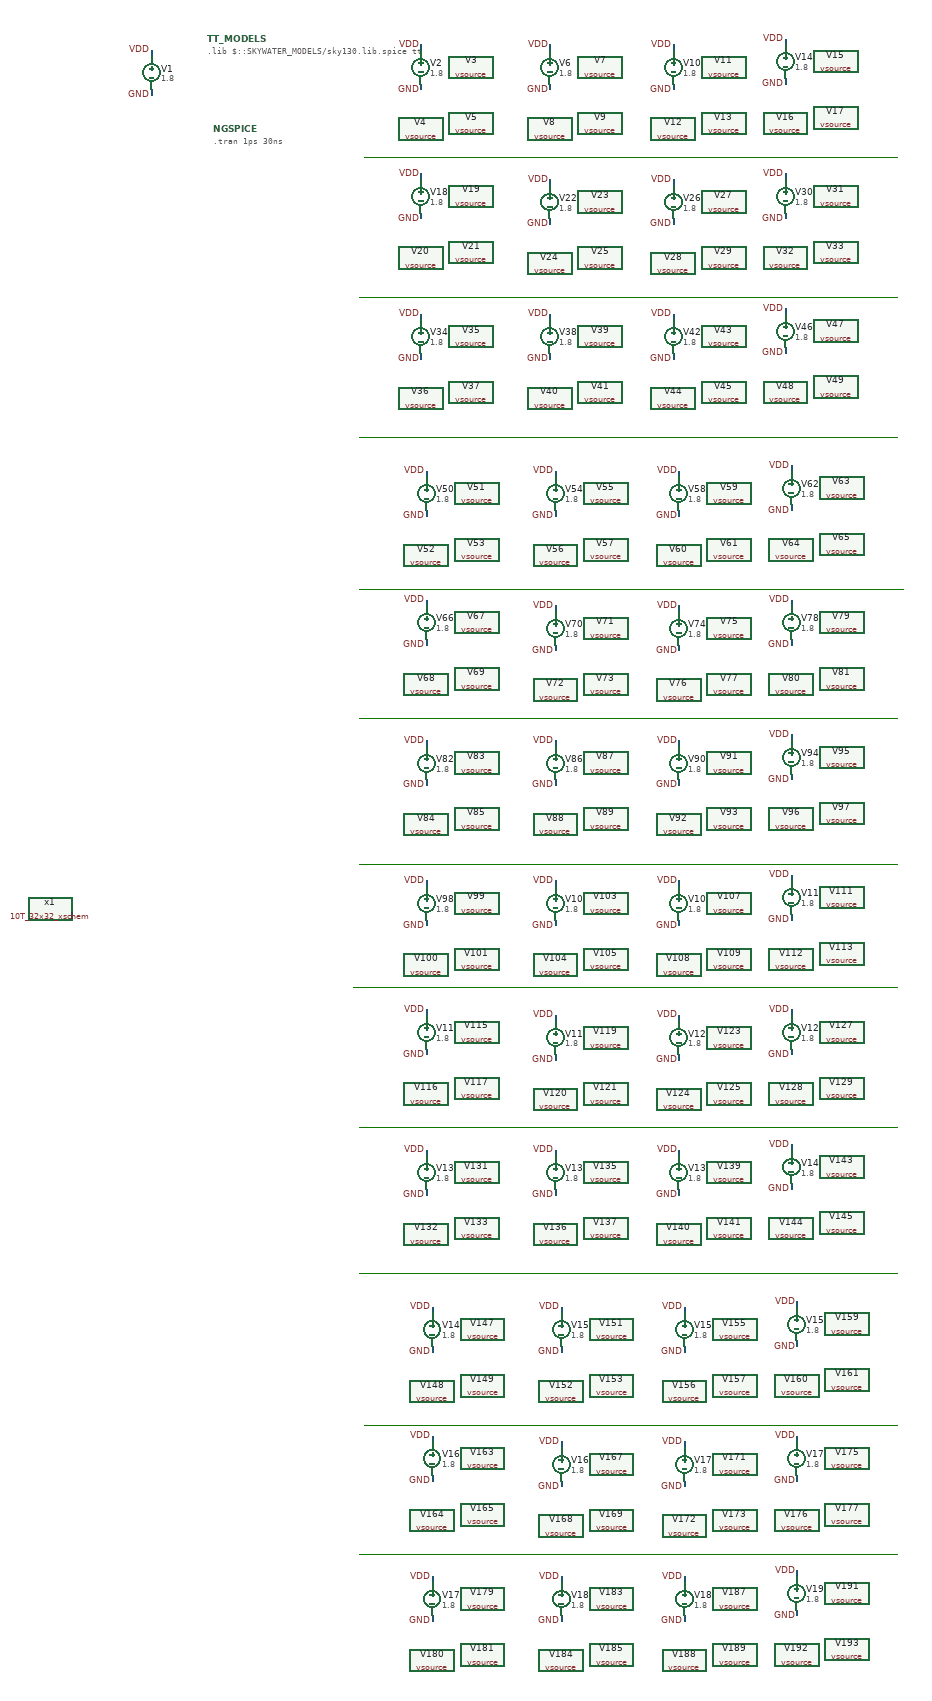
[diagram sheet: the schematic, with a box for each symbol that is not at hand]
v {xschem version=3.0.0 file_version=1.2 }
G {}
K {}
V {}
S {}
E {}
L 4 560 -1500 1510 -1500 {}
L 4 550 -1250 1510 -1250 {}
L 4 550 -1000 1510 -1000 {}
L 4 550 -730 1520 -730 {}
L 4 550 -500 1510 -500 {}
L 4 550 -240 1510 -240 {}
L 4 540 -20 1510 -20 {}
L 4 550 230 1510 230 {}
L 4 550 490 1510 490 {}
L 4 560 760 1510 760 {}
L 4 550 990 1510 990 {}
N 180 -1690 180 -1680 {
lab=VDD}
N 180 -1620 180 -1610 {
lab=GND}
N 660 -1700 660 -1690 {
lab=VDD}
N 660 -1630 660 -1620 {
lab=GND}
N 890 -1700 890 -1690 {
lab=VDD}
N 890 -1630 890 -1620 {
lab=GND}
N 1110 -1700 1110 -1690 {
lab=VDD}
N 1110 -1630 1110 -1620 {
lab=GND}
N 1310 -1710 1310 -1700 {
lab=VDD}
N 1310 -1640 1310 -1630 {
lab=GND}
N 660 -1470 660 -1460 {
lab=VDD}
N 660 -1400 660 -1390 {
lab=GND}
N 890 -1460 890 -1450 {
lab=VDD}
N 890 -1390 890 -1380 {
lab=GND}
N 1110 -1460 1110 -1450 {
lab=VDD}
N 1110 -1390 1110 -1380 {
lab=GND}
N 1310 -1470 1310 -1460 {
lab=VDD}
N 1310 -1400 1310 -1390 {
lab=GND}
N 660 -1220 660 -1210 {
lab=VDD}
N 660 -1150 660 -1140 {
lab=GND}
N 890 -1220 890 -1210 {
lab=VDD}
N 890 -1150 890 -1140 {
lab=GND}
N 1110 -1220 1110 -1210 {
lab=VDD}
N 1110 -1150 1110 -1140 {
lab=GND}
N 1310 -1230 1310 -1220 {
lab=VDD}
N 1310 -1160 1310 -1150 {
lab=GND}
N 670 -940 670 -930 {
lab=VDD}
N 670 -870 670 -860 {
lab=GND}
N 900 -940 900 -930 {
lab=VDD}
N 900 -870 900 -860 {
lab=GND}
N 1120 -940 1120 -930 {
lab=VDD}
N 1120 -870 1120 -860 {
lab=GND}
N 1320 -950 1320 -940 {
lab=VDD}
N 1320 -880 1320 -870 {
lab=GND}
N 670 -710 670 -700 {
lab=VDD}
N 670 -640 670 -630 {
lab=GND}
N 900 -700 900 -690 {
lab=VDD}
N 900 -630 900 -620 {
lab=GND}
N 1120 -700 1120 -690 {
lab=VDD}
N 1120 -630 1120 -620 {
lab=GND}
N 1320 -710 1320 -700 {
lab=VDD}
N 1320 -640 1320 -630 {
lab=GND}
N 670 -460 670 -450 {
lab=VDD}
N 670 -390 670 -380 {
lab=GND}
N 900 -460 900 -450 {
lab=VDD}
N 900 -390 900 -380 {
lab=GND}
N 1120 -460 1120 -450 {
lab=VDD}
N 1120 -390 1120 -380 {
lab=GND}
N 1320 -470 1320 -460 {
lab=VDD}
N 1320 -400 1320 -390 {
lab=GND}
N 670 -210 670 -200 {
lab=VDD}
N 670 -140 670 -130 {
lab=GND}
N 900 -210 900 -200 {
lab=VDD}
N 900 -140 900 -130 {
lab=GND}
N 1120 -210 1120 -200 {
lab=VDD}
N 1120 -140 1120 -130 {
lab=GND}
N 1320 -220 1320 -210 {
lab=VDD}
N 1320 -150 1320 -140 {
lab=GND}
N 670 20 670 30 {
lab=VDD}
N 670 90 670 100 {
lab=GND}
N 900 30 900 40 {
lab=VDD}
N 900 100 900 110 {
lab=GND}
N 1120 30 1120 40 {
lab=VDD}
N 1120 100 1120 110 {
lab=GND}
N 1320 20 1320 30 {
lab=VDD}
N 1320 90 1320 100 {
lab=GND}
N 670 270 670 280 {
lab=VDD}
N 670 340 670 350 {
lab=GND}
N 900 270 900 280 {
lab=VDD}
N 900 340 900 350 {
lab=GND}
N 1120 270 1120 280 {
lab=VDD}
N 1120 340 1120 350 {
lab=GND}
N 1320 260 1320 270 {
lab=VDD}
N 1320 330 1320 340 {
lab=GND}
N 680 550 680 560 {
lab=VDD}
N 680 620 680 630 {
lab=GND}
N 910 550 910 560 {
lab=VDD}
N 910 620 910 630 {
lab=GND}
N 1130 550 1130 560 {
lab=VDD}
N 1130 620 1130 630 {
lab=GND}
N 1330 540 1330 550 {
lab=VDD}
N 1330 610 1330 620 {
lab=GND}
N 680 780 680 790 {
lab=VDD}
N 680 850 680 860 {
lab=GND}
N 910 790 910 800 {
lab=VDD}
N 910 860 910 870 {
lab=GND}
N 1130 790 1130 800 {
lab=VDD}
N 1130 860 1130 870 {
lab=GND}
N 1330 780 1330 790 {
lab=VDD}
N 1330 850 1330 860 {
lab=GND}
N 680 1030 680 1040 {
lab=VDD}
N 680 1100 680 1110 {
lab=GND}
N 910 1030 910 1040 {
lab=VDD}
N 910 1100 910 1110 {
lab=GND}
N 1130 1030 1130 1040 {
lab=VDD}
N 1130 1100 1130 1110 {
lab=GND}
N 1330 1020 1330 1030 {
lab=VDD}
N 1330 1090 1330 1100 {
lab=GND}
C {10T_32x32_xschem.sym} 0 -160 0 0 {name=x1}
C {devices/vsource.sym} 180 -1650 0 0 {name=V1 value=1.8}
C {devices/lab_pin.sym} 180 -1690 0 0 {name=l8 sig_type=std_logic lab=VDD}
C {devices/lab_pin.sym} 180 -1610 0 0 {name=l9 sig_type=std_logic lab=GND}
C {devices/code_shown.sym} 290 -1550 0 0 {name=NGSPICE
only_toplevel=true
place=end
value="
.tran 1ps 30ns
"}
C {devices/code.sym} 280 -1710 0 0 {name=TT_MODELS
only_toplevel=true
format="tcleval( @value )"
value="
.lib $::SKYWATER_MODELS/sky130.lib.spice tt

"}
C {devices/vsource.sym} 660 -1660 0 0 {name=V2 value=1.8}
C {devices/lab_pin.sym} 660 -1700 0 0 {name=l1 sig_type=std_logic lab=VDD}
C {devices/lab_pin.sym} 660 -1620 0 0 {name=l2 sig_type=std_logic lab=GND}
C {devices/vsource.sym} 750 -1660 0 0 {name=V3 value=1.8}
C {devices/vsource.sym} 660 -1550 0 0 {name=V4 value=1.8}
C {devices/vsource.sym} 750 -1560 0 0 {name=V5 value=1.8}
C {devices/vsource.sym} 890 -1660 0 0 {name=V6 value=1.8}
C {devices/lab_pin.sym} 890 -1700 0 0 {name=l3 sig_type=std_logic lab=VDD}
C {devices/lab_pin.sym} 890 -1620 0 0 {name=l4 sig_type=std_logic lab=GND}
C {devices/vsource.sym} 980 -1660 0 0 {name=V7 value=1.8}
C {devices/vsource.sym} 890 -1550 0 0 {name=V8 value=1.8}
C {devices/vsource.sym} 980 -1560 0 0 {name=V9 value=1.8}
C {devices/vsource.sym} 1110 -1660 0 0 {name=V10 value=1.8}
C {devices/lab_pin.sym} 1110 -1700 0 0 {name=l5 sig_type=std_logic lab=VDD}
C {devices/lab_pin.sym} 1110 -1620 0 0 {name=l6 sig_type=std_logic lab=GND}
C {devices/vsource.sym} 1200 -1660 0 0 {name=V11 value=1.8}
C {devices/vsource.sym} 1110 -1550 0 0 {name=V12 value=1.8}
C {devices/vsource.sym} 1200 -1560 0 0 {name=V13 value=1.8}
C {devices/vsource.sym} 1310 -1670 0 0 {name=V14 value=1.8}
C {devices/lab_pin.sym} 1310 -1710 0 0 {name=l7 sig_type=std_logic lab=VDD}
C {devices/lab_pin.sym} 1310 -1630 0 0 {name=l10 sig_type=std_logic lab=GND}
C {devices/vsource.sym} 1400 -1670 0 0 {name=V15 value=1.8}
C {devices/vsource.sym} 1310 -1560 0 0 {name=V16 value=1.8}
C {devices/vsource.sym} 1400 -1570 0 0 {name=V17 value=1.8}
C {devices/vsource.sym} 660 -1430 0 0 {name=V18 value=1.8}
C {devices/lab_pin.sym} 660 -1470 0 0 {name=l11 sig_type=std_logic lab=VDD}
C {devices/lab_pin.sym} 660 -1390 0 0 {name=l12 sig_type=std_logic lab=GND}
C {devices/vsource.sym} 750 -1430 0 0 {name=V19 value=1.8}
C {devices/vsource.sym} 660 -1320 0 0 {name=V20 value=1.8}
C {devices/vsource.sym} 750 -1330 0 0 {name=V21 value=1.8}
C {devices/vsource.sym} 890 -1420 0 0 {name=V22 value=1.8}
C {devices/lab_pin.sym} 890 -1460 0 0 {name=l13 sig_type=std_logic lab=VDD}
C {devices/lab_pin.sym} 890 -1380 0 0 {name=l14 sig_type=std_logic lab=GND}
C {devices/vsource.sym} 980 -1420 0 0 {name=V23 value=1.8}
C {devices/vsource.sym} 890 -1310 0 0 {name=V24 value=1.8}
C {devices/vsource.sym} 980 -1320 0 0 {name=V25 value=1.8}
C {devices/vsource.sym} 1110 -1420 0 0 {name=V26 value=1.8}
C {devices/lab_pin.sym} 1110 -1460 0 0 {name=l15 sig_type=std_logic lab=VDD}
C {devices/lab_pin.sym} 1110 -1380 0 0 {name=l16 sig_type=std_logic lab=GND}
C {devices/vsource.sym} 1200 -1420 0 0 {name=V27 value=1.8}
C {devices/vsource.sym} 1110 -1310 0 0 {name=V28 value=1.8}
C {devices/vsource.sym} 1200 -1320 0 0 {name=V29 value=1.8}
C {devices/vsource.sym} 1310 -1430 0 0 {name=V30 value=1.8}
C {devices/lab_pin.sym} 1310 -1470 0 0 {name=l17 sig_type=std_logic lab=VDD}
C {devices/lab_pin.sym} 1310 -1390 0 0 {name=l18 sig_type=std_logic lab=GND}
C {devices/vsource.sym} 1400 -1430 0 0 {name=V31 value=1.8}
C {devices/vsource.sym} 1310 -1320 0 0 {name=V32 value=1.8}
C {devices/vsource.sym} 1400 -1330 0 0 {name=V33 value=1.8}
C {devices/vsource.sym} 660 -1180 0 0 {name=V34 value=1.8}
C {devices/lab_pin.sym} 660 -1220 0 0 {name=l19 sig_type=std_logic lab=VDD}
C {devices/lab_pin.sym} 660 -1140 0 0 {name=l20 sig_type=std_logic lab=GND}
C {devices/vsource.sym} 750 -1180 0 0 {name=V35 value=1.8}
C {devices/vsource.sym} 660 -1070 0 0 {name=V36 value=1.8}
C {devices/vsource.sym} 750 -1080 0 0 {name=V37 value=1.8}
C {devices/vsource.sym} 890 -1180 0 0 {name=V38 value=1.8}
C {devices/lab_pin.sym} 890 -1220 0 0 {name=l21 sig_type=std_logic lab=VDD}
C {devices/lab_pin.sym} 890 -1140 0 0 {name=l22 sig_type=std_logic lab=GND}
C {devices/vsource.sym} 980 -1180 0 0 {name=V39 value=1.8}
C {devices/vsource.sym} 890 -1070 0 0 {name=V40 value=1.8}
C {devices/vsource.sym} 980 -1080 0 0 {name=V41 value=1.8}
C {devices/vsource.sym} 1110 -1180 0 0 {name=V42 value=1.8}
C {devices/lab_pin.sym} 1110 -1220 0 0 {name=l23 sig_type=std_logic lab=VDD}
C {devices/lab_pin.sym} 1110 -1140 0 0 {name=l24 sig_type=std_logic lab=GND}
C {devices/vsource.sym} 1200 -1180 0 0 {name=V43 value=1.8}
C {devices/vsource.sym} 1110 -1070 0 0 {name=V44 value=1.8}
C {devices/vsource.sym} 1200 -1080 0 0 {name=V45 value=1.8}
C {devices/vsource.sym} 1310 -1190 0 0 {name=V46 value=1.8}
C {devices/lab_pin.sym} 1310 -1230 0 0 {name=l25 sig_type=std_logic lab=VDD}
C {devices/lab_pin.sym} 1310 -1150 0 0 {name=l26 sig_type=std_logic lab=GND}
C {devices/vsource.sym} 1400 -1190 0 0 {name=V47 value=1.8}
C {devices/vsource.sym} 1310 -1080 0 0 {name=V48 value=1.8}
C {devices/vsource.sym} 1400 -1090 0 0 {name=V49 value=1.8}
C {devices/vsource.sym} 670 -900 0 0 {name=V50 value=1.8}
C {devices/lab_pin.sym} 670 -940 0 0 {name=l27 sig_type=std_logic lab=VDD}
C {devices/lab_pin.sym} 670 -860 0 0 {name=l28 sig_type=std_logic lab=GND}
C {devices/vsource.sym} 760 -900 0 0 {name=V51 value=1.8}
C {devices/vsource.sym} 670 -790 0 0 {name=V52 value=1.8}
C {devices/vsource.sym} 760 -800 0 0 {name=V53 value=1.8}
C {devices/vsource.sym} 900 -900 0 0 {name=V54 value=1.8}
C {devices/lab_pin.sym} 900 -940 0 0 {name=l29 sig_type=std_logic lab=VDD}
C {devices/lab_pin.sym} 900 -860 0 0 {name=l30 sig_type=std_logic lab=GND}
C {devices/vsource.sym} 990 -900 0 0 {name=V55 value=1.8}
C {devices/vsource.sym} 900 -790 0 0 {name=V56 value=1.8}
C {devices/vsource.sym} 990 -800 0 0 {name=V57 value=1.8}
C {devices/vsource.sym} 1120 -900 0 0 {name=V58 value=1.8}
C {devices/lab_pin.sym} 1120 -940 0 0 {name=l31 sig_type=std_logic lab=VDD}
C {devices/lab_pin.sym} 1120 -860 0 0 {name=l32 sig_type=std_logic lab=GND}
C {devices/vsource.sym} 1210 -900 0 0 {name=V59 value=1.8}
C {devices/vsource.sym} 1120 -790 0 0 {name=V60 value=1.8}
C {devices/vsource.sym} 1210 -800 0 0 {name=V61 value=1.8}
C {devices/vsource.sym} 1320 -910 0 0 {name=V62 value=1.8}
C {devices/lab_pin.sym} 1320 -950 0 0 {name=l33 sig_type=std_logic lab=VDD}
C {devices/lab_pin.sym} 1320 -870 0 0 {name=l34 sig_type=std_logic lab=GND}
C {devices/vsource.sym} 1410 -910 0 0 {name=V63 value=1.8}
C {devices/vsource.sym} 1320 -800 0 0 {name=V64 value=1.8}
C {devices/vsource.sym} 1410 -810 0 0 {name=V65 value=1.8}
C {devices/vsource.sym} 670 -670 0 0 {name=V66 value=1.8}
C {devices/lab_pin.sym} 670 -710 0 0 {name=l35 sig_type=std_logic lab=VDD}
C {devices/lab_pin.sym} 670 -630 0 0 {name=l36 sig_type=std_logic lab=GND}
C {devices/vsource.sym} 760 -670 0 0 {name=V67 value=1.8}
C {devices/vsource.sym} 670 -560 0 0 {name=V68 value=1.8}
C {devices/vsource.sym} 760 -570 0 0 {name=V69 value=1.8}
C {devices/vsource.sym} 900 -660 0 0 {name=V70 value=1.8}
C {devices/lab_pin.sym} 900 -700 0 0 {name=l37 sig_type=std_logic lab=VDD}
C {devices/lab_pin.sym} 900 -620 0 0 {name=l38 sig_type=std_logic lab=GND}
C {devices/vsource.sym} 990 -660 0 0 {name=V71 value=1.8}
C {devices/vsource.sym} 900 -550 0 0 {name=V72 value=1.8}
C {devices/vsource.sym} 990 -560 0 0 {name=V73 value=1.8}
C {devices/vsource.sym} 1120 -660 0 0 {name=V74 value=1.8}
C {devices/lab_pin.sym} 1120 -700 0 0 {name=l39 sig_type=std_logic lab=VDD}
C {devices/lab_pin.sym} 1120 -620 0 0 {name=l40 sig_type=std_logic lab=GND}
C {devices/vsource.sym} 1210 -660 0 0 {name=V75 value=1.8}
C {devices/vsource.sym} 1120 -550 0 0 {name=V76 value=1.8}
C {devices/vsource.sym} 1210 -560 0 0 {name=V77 value=1.8}
C {devices/vsource.sym} 1320 -670 0 0 {name=V78 value=1.8}
C {devices/lab_pin.sym} 1320 -710 0 0 {name=l41 sig_type=std_logic lab=VDD}
C {devices/lab_pin.sym} 1320 -630 0 0 {name=l42 sig_type=std_logic lab=GND}
C {devices/vsource.sym} 1410 -670 0 0 {name=V79 value=1.8}
C {devices/vsource.sym} 1320 -560 0 0 {name=V80 value=1.8}
C {devices/vsource.sym} 1410 -570 0 0 {name=V81 value=1.8}
C {devices/vsource.sym} 670 -420 0 0 {name=V82 value=1.8}
C {devices/lab_pin.sym} 670 -460 0 0 {name=l43 sig_type=std_logic lab=VDD}
C {devices/lab_pin.sym} 670 -380 0 0 {name=l44 sig_type=std_logic lab=GND}
C {devices/vsource.sym} 760 -420 0 0 {name=V83 value=1.8}
C {devices/vsource.sym} 670 -310 0 0 {name=V84 value=1.8}
C {devices/vsource.sym} 760 -320 0 0 {name=V85 value=1.8}
C {devices/vsource.sym} 900 -420 0 0 {name=V86 value=1.8}
C {devices/lab_pin.sym} 900 -460 0 0 {name=l45 sig_type=std_logic lab=VDD}
C {devices/lab_pin.sym} 900 -380 0 0 {name=l46 sig_type=std_logic lab=GND}
C {devices/vsource.sym} 990 -420 0 0 {name=V87 value=1.8}
C {devices/vsource.sym} 900 -310 0 0 {name=V88 value=1.8}
C {devices/vsource.sym} 990 -320 0 0 {name=V89 value=1.8}
C {devices/vsource.sym} 1120 -420 0 0 {name=V90 value=1.8}
C {devices/lab_pin.sym} 1120 -460 0 0 {name=l47 sig_type=std_logic lab=VDD}
C {devices/lab_pin.sym} 1120 -380 0 0 {name=l48 sig_type=std_logic lab=GND}
C {devices/vsource.sym} 1210 -420 0 0 {name=V91 value=1.8}
C {devices/vsource.sym} 1120 -310 0 0 {name=V92 value=1.8}
C {devices/vsource.sym} 1210 -320 0 0 {name=V93 value=1.8}
C {devices/vsource.sym} 1320 -430 0 0 {name=V94 value=1.8}
C {devices/lab_pin.sym} 1320 -470 0 0 {name=l49 sig_type=std_logic lab=VDD}
C {devices/lab_pin.sym} 1320 -390 0 0 {name=l50 sig_type=std_logic lab=GND}
C {devices/vsource.sym} 1410 -430 0 0 {name=V95 value=1.8}
C {devices/vsource.sym} 1320 -320 0 0 {name=V96 value=1.8}
C {devices/vsource.sym} 1410 -330 0 0 {name=V97 value=1.8}
C {devices/vsource.sym} 670 -170 0 0 {name=V98 value=1.8}
C {devices/lab_pin.sym} 670 -210 0 0 {name=l51 sig_type=std_logic lab=VDD}
C {devices/lab_pin.sym} 670 -130 0 0 {name=l52 sig_type=std_logic lab=GND}
C {devices/vsource.sym} 760 -170 0 0 {name=V99 value=1.8}
C {devices/vsource.sym} 670 -60 0 0 {name=V100 value=1.8}
C {devices/vsource.sym} 760 -70 0 0 {name=V101 value=1.8}
C {devices/vsource.sym} 900 -170 0 0 {name=V102 value=1.8}
C {devices/lab_pin.sym} 900 -210 0 0 {name=l53 sig_type=std_logic lab=VDD}
C {devices/lab_pin.sym} 900 -130 0 0 {name=l54 sig_type=std_logic lab=GND}
C {devices/vsource.sym} 990 -170 0 0 {name=V103 value=1.8}
C {devices/vsource.sym} 900 -60 0 0 {name=V104 value=1.8}
C {devices/vsource.sym} 990 -70 0 0 {name=V105 value=1.8}
C {devices/vsource.sym} 1120 -170 0 0 {name=V106 value=1.8}
C {devices/lab_pin.sym} 1120 -210 0 0 {name=l55 sig_type=std_logic lab=VDD}
C {devices/lab_pin.sym} 1120 -130 0 0 {name=l56 sig_type=std_logic lab=GND}
C {devices/vsource.sym} 1210 -170 0 0 {name=V107 value=1.8}
C {devices/vsource.sym} 1120 -60 0 0 {name=V108 value=1.8}
C {devices/vsource.sym} 1210 -70 0 0 {name=V109 value=1.8}
C {devices/vsource.sym} 1320 -180 0 0 {name=V110 value=1.8}
C {devices/lab_pin.sym} 1320 -220 0 0 {name=l57 sig_type=std_logic lab=VDD}
C {devices/lab_pin.sym} 1320 -140 0 0 {name=l58 sig_type=std_logic lab=GND}
C {devices/vsource.sym} 1410 -180 0 0 {name=V111 value=1.8}
C {devices/vsource.sym} 1320 -70 0 0 {name=V112 value=1.8}
C {devices/vsource.sym} 1410 -80 0 0 {name=V113 value=1.8}
C {devices/vsource.sym} 670 60 0 0 {name=V114 value=1.8}
C {devices/lab_pin.sym} 670 20 0 0 {name=l59 sig_type=std_logic lab=VDD}
C {devices/lab_pin.sym} 670 100 0 0 {name=l60 sig_type=std_logic lab=GND}
C {devices/vsource.sym} 760 60 0 0 {name=V115 value=1.8}
C {devices/vsource.sym} 670 170 0 0 {name=V116 value=1.8}
C {devices/vsource.sym} 760 160 0 0 {name=V117 value=1.8}
C {devices/vsource.sym} 900 70 0 0 {name=V118 value=1.8}
C {devices/lab_pin.sym} 900 30 0 0 {name=l61 sig_type=std_logic lab=VDD}
C {devices/lab_pin.sym} 900 110 0 0 {name=l62 sig_type=std_logic lab=GND}
C {devices/vsource.sym} 990 70 0 0 {name=V119 value=1.8}
C {devices/vsource.sym} 900 180 0 0 {name=V120 value=1.8}
C {devices/vsource.sym} 990 170 0 0 {name=V121 value=1.8}
C {devices/vsource.sym} 1120 70 0 0 {name=V122 value=1.8}
C {devices/lab_pin.sym} 1120 30 0 0 {name=l63 sig_type=std_logic lab=VDD}
C {devices/lab_pin.sym} 1120 110 0 0 {name=l64 sig_type=std_logic lab=GND}
C {devices/vsource.sym} 1210 70 0 0 {name=V123 value=1.8}
C {devices/vsource.sym} 1120 180 0 0 {name=V124 value=1.8}
C {devices/vsource.sym} 1210 170 0 0 {name=V125 value=1.8}
C {devices/vsource.sym} 1320 60 0 0 {name=V126 value=1.8}
C {devices/lab_pin.sym} 1320 20 0 0 {name=l65 sig_type=std_logic lab=VDD}
C {devices/lab_pin.sym} 1320 100 0 0 {name=l66 sig_type=std_logic lab=GND}
C {devices/vsource.sym} 1410 60 0 0 {name=V127 value=1.8}
C {devices/vsource.sym} 1320 170 0 0 {name=V128 value=1.8}
C {devices/vsource.sym} 1410 160 0 0 {name=V129 value=1.8}
C {devices/vsource.sym} 670 310 0 0 {name=V130 value=1.8}
C {devices/lab_pin.sym} 670 270 0 0 {name=l67 sig_type=std_logic lab=VDD}
C {devices/lab_pin.sym} 670 350 0 0 {name=l68 sig_type=std_logic lab=GND}
C {devices/vsource.sym} 760 310 0 0 {name=V131 value=1.8}
C {devices/vsource.sym} 670 420 0 0 {name=V132 value=1.8}
C {devices/vsource.sym} 760 410 0 0 {name=V133 value=1.8}
C {devices/vsource.sym} 900 310 0 0 {name=V134 value=1.8}
C {devices/lab_pin.sym} 900 270 0 0 {name=l69 sig_type=std_logic lab=VDD}
C {devices/lab_pin.sym} 900 350 0 0 {name=l70 sig_type=std_logic lab=GND}
C {devices/vsource.sym} 990 310 0 0 {name=V135 value=1.8}
C {devices/vsource.sym} 900 420 0 0 {name=V136 value=1.8}
C {devices/vsource.sym} 990 410 0 0 {name=V137 value=1.8}
C {devices/vsource.sym} 1120 310 0 0 {name=V138 value=1.8}
C {devices/lab_pin.sym} 1120 270 0 0 {name=l71 sig_type=std_logic lab=VDD}
C {devices/lab_pin.sym} 1120 350 0 0 {name=l72 sig_type=std_logic lab=GND}
C {devices/vsource.sym} 1210 310 0 0 {name=V139 value=1.8}
C {devices/vsource.sym} 1120 420 0 0 {name=V140 value=1.8}
C {devices/vsource.sym} 1210 410 0 0 {name=V141 value=1.8}
C {devices/vsource.sym} 1320 300 0 0 {name=V142 value=1.8}
C {devices/lab_pin.sym} 1320 260 0 0 {name=l73 sig_type=std_logic lab=VDD}
C {devices/lab_pin.sym} 1320 340 0 0 {name=l74 sig_type=std_logic lab=GND}
C {devices/vsource.sym} 1410 300 0 0 {name=V143 value=1.8}
C {devices/vsource.sym} 1320 410 0 0 {name=V144 value=1.8}
C {devices/vsource.sym} 1410 400 0 0 {name=V145 value=1.8}
C {devices/vsource.sym} 680 590 0 0 {name=V146 value=1.8}
C {devices/lab_pin.sym} 680 550 0 0 {name=l75 sig_type=std_logic lab=VDD}
C {devices/lab_pin.sym} 680 630 0 0 {name=l76 sig_type=std_logic lab=GND}
C {devices/vsource.sym} 770 590 0 0 {name=V147 value=1.8}
C {devices/vsource.sym} 680 700 0 0 {name=V148 value=1.8}
C {devices/vsource.sym} 770 690 0 0 {name=V149 value=1.8}
C {devices/vsource.sym} 910 590 0 0 {name=V150 value=1.8}
C {devices/lab_pin.sym} 910 550 0 0 {name=l77 sig_type=std_logic lab=VDD}
C {devices/lab_pin.sym} 910 630 0 0 {name=l78 sig_type=std_logic lab=GND}
C {devices/vsource.sym} 1000 590 0 0 {name=V151 value=1.8}
C {devices/vsource.sym} 910 700 0 0 {name=V152 value=1.8}
C {devices/vsource.sym} 1000 690 0 0 {name=V153 value=1.8}
C {devices/vsource.sym} 1130 590 0 0 {name=V154 value=1.8}
C {devices/lab_pin.sym} 1130 550 0 0 {name=l79 sig_type=std_logic lab=VDD}
C {devices/lab_pin.sym} 1130 630 0 0 {name=l80 sig_type=std_logic lab=GND}
C {devices/vsource.sym} 1220 590 0 0 {name=V155 value=1.8}
C {devices/vsource.sym} 1130 700 0 0 {name=V156 value=1.8}
C {devices/vsource.sym} 1220 690 0 0 {name=V157 value=1.8}
C {devices/vsource.sym} 1330 580 0 0 {name=V158 value=1.8}
C {devices/lab_pin.sym} 1330 540 0 0 {name=l81 sig_type=std_logic lab=VDD}
C {devices/lab_pin.sym} 1330 620 0 0 {name=l82 sig_type=std_logic lab=GND}
C {devices/vsource.sym} 1420 580 0 0 {name=V159 value=1.8}
C {devices/vsource.sym} 1330 690 0 0 {name=V160 value=1.8}
C {devices/vsource.sym} 1420 680 0 0 {name=V161 value=1.8}
C {devices/vsource.sym} 680 820 0 0 {name=V162 value=1.8}
C {devices/lab_pin.sym} 680 780 0 0 {name=l83 sig_type=std_logic lab=VDD}
C {devices/lab_pin.sym} 680 860 0 0 {name=l84 sig_type=std_logic lab=GND}
C {devices/vsource.sym} 770 820 0 0 {name=V163 value=1.8}
C {devices/vsource.sym} 680 930 0 0 {name=V164 value=1.8}
C {devices/vsource.sym} 770 920 0 0 {name=V165 value=1.8}
C {devices/vsource.sym} 910 830 0 0 {name=V166 value=1.8}
C {devices/lab_pin.sym} 910 790 0 0 {name=l85 sig_type=std_logic lab=VDD}
C {devices/lab_pin.sym} 910 870 0 0 {name=l86 sig_type=std_logic lab=GND}
C {devices/vsource.sym} 1000 830 0 0 {name=V167 value=1.8}
C {devices/vsource.sym} 910 940 0 0 {name=V168 value=1.8}
C {devices/vsource.sym} 1000 930 0 0 {name=V169 value=1.8}
C {devices/vsource.sym} 1130 830 0 0 {name=V170 value=1.8}
C {devices/lab_pin.sym} 1130 790 0 0 {name=l87 sig_type=std_logic lab=VDD}
C {devices/lab_pin.sym} 1130 870 0 0 {name=l88 sig_type=std_logic lab=GND}
C {devices/vsource.sym} 1220 830 0 0 {name=V171 value=1.8}
C {devices/vsource.sym} 1130 940 0 0 {name=V172 value=1.8}
C {devices/vsource.sym} 1220 930 0 0 {name=V173 value=1.8}
C {devices/vsource.sym} 1330 820 0 0 {name=V174 value=1.8}
C {devices/lab_pin.sym} 1330 780 0 0 {name=l89 sig_type=std_logic lab=VDD}
C {devices/lab_pin.sym} 1330 860 0 0 {name=l90 sig_type=std_logic lab=GND}
C {devices/vsource.sym} 1420 820 0 0 {name=V175 value=1.8}
C {devices/vsource.sym} 1330 930 0 0 {name=V176 value=1.8}
C {devices/vsource.sym} 1420 920 0 0 {name=V177 value=1.8}
C {devices/vsource.sym} 680 1070 0 0 {name=V178 value=1.8}
C {devices/lab_pin.sym} 680 1030 0 0 {name=l91 sig_type=std_logic lab=VDD}
C {devices/lab_pin.sym} 680 1110 0 0 {name=l92 sig_type=std_logic lab=GND}
C {devices/vsource.sym} 770 1070 0 0 {name=V179 value=1.8}
C {devices/vsource.sym} 680 1180 0 0 {name=V180 value=1.8}
C {devices/vsource.sym} 770 1170 0 0 {name=V181 value=1.8}
C {devices/vsource.sym} 910 1070 0 0 {name=V182 value=1.8}
C {devices/lab_pin.sym} 910 1030 0 0 {name=l93 sig_type=std_logic lab=VDD}
C {devices/lab_pin.sym} 910 1110 0 0 {name=l94 sig_type=std_logic lab=GND}
C {devices/vsource.sym} 1000 1070 0 0 {name=V183 value=1.8}
C {devices/vsource.sym} 910 1180 0 0 {name=V184 value=1.8}
C {devices/vsource.sym} 1000 1170 0 0 {name=V185 value=1.8}
C {devices/vsource.sym} 1130 1070 0 0 {name=V186 value=1.8}
C {devices/lab_pin.sym} 1130 1030 0 0 {name=l95 sig_type=std_logic lab=VDD}
C {devices/lab_pin.sym} 1130 1110 0 0 {name=l96 sig_type=std_logic lab=GND}
C {devices/vsource.sym} 1220 1070 0 0 {name=V187 value=1.8}
C {devices/vsource.sym} 1130 1180 0 0 {name=V188 value=1.8}
C {devices/vsource.sym} 1220 1170 0 0 {name=V189 value=1.8}
C {devices/vsource.sym} 1330 1060 0 0 {name=V190 value=1.8}
C {devices/lab_pin.sym} 1330 1020 0 0 {name=l97 sig_type=std_logic lab=VDD}
C {devices/lab_pin.sym} 1330 1100 0 0 {name=l98 sig_type=std_logic lab=GND}
C {devices/vsource.sym} 1420 1060 0 0 {name=V191 value=1.8}
C {devices/vsource.sym} 1330 1170 0 0 {name=V192 value=1.8}
C {devices/vsource.sym} 1420 1160 0 0 {name=V193 value=1.8}
